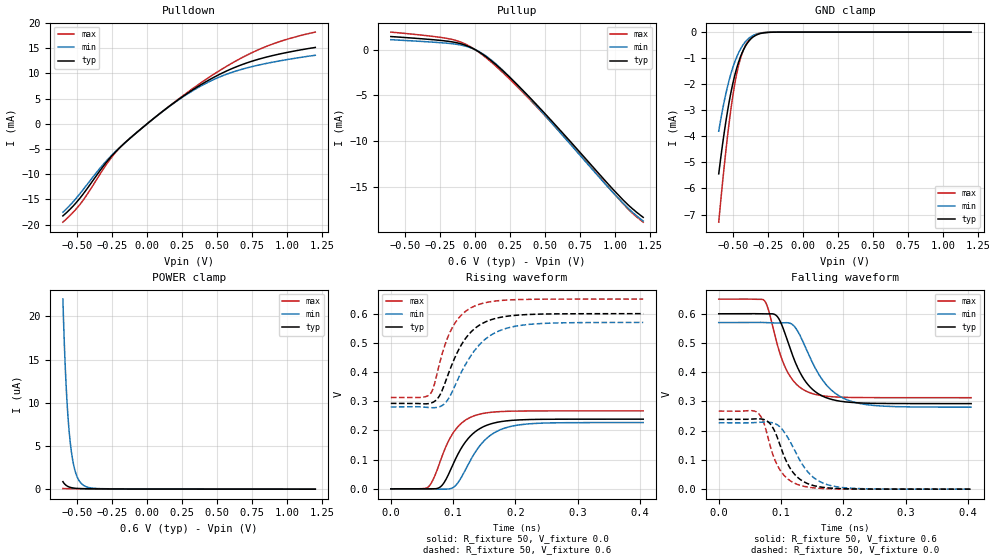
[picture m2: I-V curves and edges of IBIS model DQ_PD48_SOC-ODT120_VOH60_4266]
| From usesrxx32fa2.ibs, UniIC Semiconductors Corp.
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| DQ_PD48_SOC-ODT120_VOH60_4266
| (48 Ohm Pulldown, 120 Ohm System ODT Setting, VOH=VDDQ*0.60, 3200-4266Mbps)
[Model]   DQ_PD48_SOC-ODT120_VOH60_4266
Model_type   I/O
Vinl = 120.000mV
Vinh = 240.000mV
Vmeas = 180.000mV
Vref = 0.0mV
Cref = 0.0pF
Rref = 120.000Ohm
|   typ   min   max
|C_comp   0.834pF   0.784pF   0.884pF
C_comp_pullup   0.4170pF   0.3920pF   0.4420pF
C_comp_pulldown   0.4170pF   0.3920pF   0.4420pF
| Note: C_comp changes when the ODT circuit is enabled.
[Model Spec]
| Input threshold voltage corners
Vinl   0.1200V   0.1110V   0.1350V
Vinh   0.2400V   0.2310V   0.2550V
| Measurement voltage corners
Vmeas   0.1800V   0.1710V   0.1950V
| Timing spec test load voltage corners
Vref   0.0000V   0.0000V   0.0000V
| Dynamic Overshoot Parameters from LPDDR4_0P6 Specification
D_overshoot_ampl_h   0.30   NA   NA
D_overshoot_ampl_l   0.30   NA   NA
D_overshoot_area_h   0.1n   NA   NA
D_overshoot_area_l   0.1n   NA   NA
[Voltage Range]   0.6000V   0.5700V   0.6500V
[Pullup Reference]   0.6000V   0.5700V   0.6500V
| Junction Temperature (Ambient temp is 35C typ 95C min -40C max)
[Temperature Range]   50.0   110.0   -40.0
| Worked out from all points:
|   slope of the pulldown table from 0 to 0.09 V, typ, clamps not added: 44.5 ohm
|   slope of the pullup table from 0 to 0.09 V, typ, clamps not added: 98.8 ohm
|   GND clamp passes 1 mA (typ) near -0.45 V on its own axis
|   rising waveform, R_fixture 50, V_fixture 0.0: 20-80 % time 40.6ps typ, 44ps min, 35.7ps max; typ from 0 V to 0.239 V
|   falling waveform, R_fixture 50, V_fixture 0.6: 20-80 % time 39.2ps typ, 47.5ps min, 32.6ps max; typ from 0.6 V to 0.293 V
|   rising waveform, R_fixture 50, V_fixture 0.6: 20-80 % time 43.7ps typ, 51.6ps min, 35.4ps max; typ from 0.293 V to 0.6 V
|   falling waveform, R_fixture 50, V_fixture 0.0: 20-80 % time 31.7ps typ, 39.8ps min, 28.1ps max; typ from 0.239 V to 0 V
[Pulldown]
|   Voltage   I(typ)   I(min)   I(max)
-600mV    -18.26mA   -17.54mA   -19.51mA
-531.6mV  -16.44mA   -15.6mA    -17.67mA
-472.2mV  -14.52mA   -13.63mA   -15.77mA
-281.4mV  -7.339mA   -7.093mA   -7.724mA
-189.6mV  -4.59mA    -4.57mA    -4.601mA
85.8mV    1.925mA    1.914mA    1.931mA
310.8mV   6.479mA    6.321mA    6.697mA
417mV     8.313mA    8.002mA    8.761mA
525mV     9.929mA    9.39mA     10.7mA
764.4mV   12.57mA    11.46mA    14.34mA
971.4mV   14.02mA    12.62mA    16.55mA
1.2V      15.16mA    13.61mA    18.21mA
[GND Clamp]
|   Voltage   I(typ)   I(min)   I(max)
-600mV    -5.44mA    -3.802mA   -7.294mA
-567.6mV  -4.11mA    -2.837mA   -5.5mA
-535.2mV  -2.973mA   -2.046mA   -3.902mA
-506.4mV  -2.147mA   -1.48mA    -2.701mA
-481.2mV  -1.571mA   -1.083mA   -1.86mA
-454.2mV  -1.087mA   -747.7uA   -1.192mA
-421.8mV  -660.2uA   -454.9uA   -659.7uA
-389.4mV  -377uA     -257.1uA   -339.9uA
-357mV    -197.1uA   -136.6uA   -159.9uA
-292.2mV  -42.68uA   -31.8uA    -26.85uA
-195mV    -2.516uA   -2.429uA   -874.8nA
1.2V      0A         0A         0A
[Pullup]
|   Voltage   I(typ)   I(min)   I(max)
-600mV    1.424mA    1.081mA    1.912mA
-294mV    1.07mA     804.2uA    1.43mA
-146.4mV  795.9uA    607.4uA    1.042mA
-83.4mV   553.2uA    438.5uA    703.4uA
-18.6mV   146.8uA    121.9uA    180.2uA
87.6mV    -883.2uA   -806.4uA   -1.004mA
226.2mV   -2.721mA   -2.68mA    -2.925mA
413.4mV   -5.611mA   -5.73mA    -5.835mA
656.4mV   -9.666mA   -9.948mA   -9.9mA
980.4mV   -15.24mA   -15.59mA   -15.58mA
1.106V    -17.21mA   -17.58mA   -17.68mA
1.2V      -18.38mA   -18.78mA   -18.91mA
[POWER Clamp]
|   Voltage   I(typ)   I(min)   I(max)
-600mV    870.6nA    21.99uA    72.65nA
-594.6mV  739.5nA    19.12uA    70.4nA
-587.4mV  597.8nA    15.82uA    68.09nA
-574.8mV  417.8nA    11.31uA    64.22nA
-560.4mV  285.4nA    7.67uA     60.04nA
-546mV    201.7nA    5.188uA    56.09nA
-531.6mV  149nA      3.499uA    52.35nA
-511.8mV  105.9nA    2.043uA    47.56nA
-486.6mV  77.09nA    1.04uA     41.97nA
-456mV    59.8nA     477.6nA    35.93nA
-312mV    32.54nA    54.19nA    16.21nA
1.2V      0A         0A         0A
[Ramp]
|   typ   min   max
| 20% - 80%
dV/dt_r   143.21m/40.59p   136.24m/44.02p   160.27m/35.72p
dV/dt_f   184.34m/39.19p   173.66m/47.54p   202.23m/32.56p
| 25% - 75%
|dV/dt_r   119.34m/32.17p   113.54m/34.89p   133.56m/28.20p
|dV/dt_f   153.62m/30.99p   144.72m/37.66p   168.52m/25.70p
R_load = 50
[Rising Waveform]
R_fixture = 50
V_fixture = 0.0
|   Time   V(typ)   V(min)   V(max)
0s        75.42uV    60.11uV    39.23uV
58ps      -11.71uV   183.3uV    3.548mV
67ps      126.2uV    -347.1uV   28.22mV
79ps      6.01mV     -850.5uV   92.77mV
91ps      42.64mV    -691.5uV   157mV
104ps     103.1mV    11.71mV    203.5mV
135ps     195mV      124.1mV    251.2mV
162ps     223.6mV    186.7mV    262.5mV
199ps     235.4mV    216.8mV    266.3mV
405ps     238.8mV    227.1mV    267.2mV
[Falling Waveform]
R_fixture   = 50
V_fixture   = 0.6
V_fixture_min = 0.57
V_fixture_max = 0.65
|   Time   V(typ)   V(min)   V(max)
0s        600mV      570mV      650mV
73ps      599.6mV    570.2mV    645.9mV
80ps      599.8mV    569.5mV    611.9mV
93ps      592.9mV    568.4mV    502.6mV
108ps     522.5mV    569.6mV    410.9mV
124ps     428.2mV    549.7mV    360.2mV
144ps     355.6mV    462.4mV    331.7mV
174ps     311.7mV    353.6mV    317.7mV
214ps     296.6mV    299.6mV    313.7mV
405ps     292.8mV    280.6mV    313mV
[Rising Waveform]
R_fixture   = 50
V_fixture   = 0.6
V_fixture_min = 0.57
V_fixture_max = 0.65
|   Time   V(typ)   V(min)   V(max)
0s        292.7mV    280.5mV    312.9mV
63ps      293mV      278.3mV    324.5mV
69ps      298.1mV    278mV      351.2mV
78ps      318.4mV    281.1mV    428mV
97ps      420.1mV    326.2mV    545.4mV
115ps     499.7mV    407.1mV    598.9mV
135ps     549.7mV    475.5mV    626.7mV
163ps     580.7mV    529.5mV    642mV
203ps     595mV      558.1mV    648.2mV
405ps     600mV      570mV      650mV
[Falling Waveform]
R_fixture = 50
V_fixture = 0.0
|   Time   V(typ)   V(min)   V(max)
0s        238.8mV    227.2mV    267.2mV
63ps      240.8mV    228.7mV    260.7mV
72ps      238.5mV    229.7mV    229mV
82ps      224.9mV    228.8mV    151.6mV
96ps      165.3mV    217.1mV    73.97mV
112ps     81.03mV    172.2mV    33.08mV
130ps     34.46mV    99.54mV    13.53mV
154ps     11.34mV    36.95mV    4.158mV
187ps     2.651mV    9.038mV    888.7uV
405ps     143.9uV    152.4uV    60.13uV
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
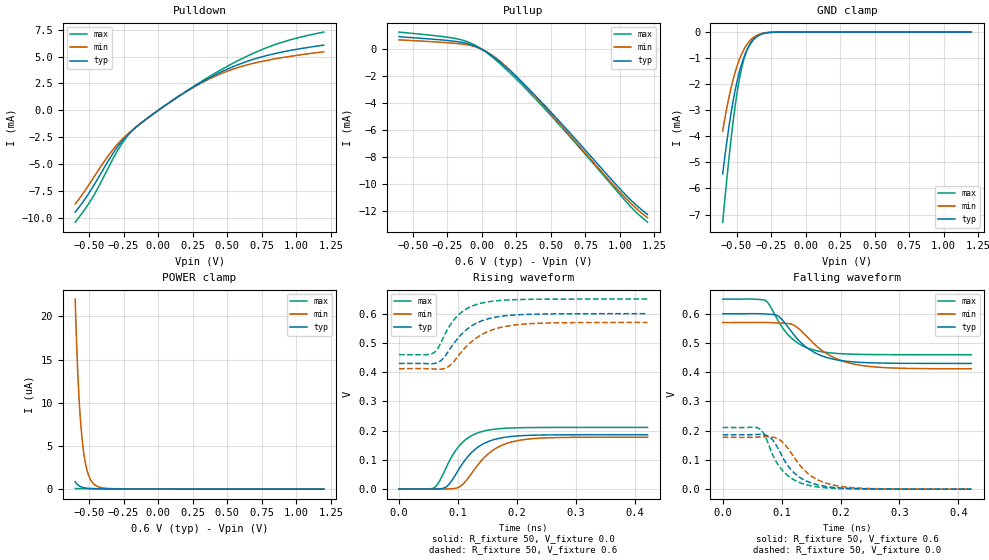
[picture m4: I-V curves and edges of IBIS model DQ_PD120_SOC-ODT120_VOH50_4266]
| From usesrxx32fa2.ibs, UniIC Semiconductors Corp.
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| DQ_PD120_SOC-ODT120_VOH50_4266
| (120 Ohm Pulldown, 120 Ohm System ODT Setting, VOH=VDDQ*0.50, 3200-4266Mbps)
[Model]   DQ_PD120_SOC-ODT120_VOH50_4266
Model_type   I/O
Vinl = 90.000mV
Vinh = 210.000mV
Vmeas = 150.000mV
Vref = 0.0mV
Cref = 0.0pF
Rref = 120.000Ohm
|   typ   min   max
|C_comp   0.834pF   0.784pF   0.884pF
C_comp_pullup   0.4170pF   0.3920pF   0.4420pF
C_comp_pulldown   0.4170pF   0.3920pF   0.4420pF
| Note: C_comp changes when the ODT circuit is enabled.
[Model Spec]
| Input threshold voltage corners
Vinl   0.0900V   0.0825V   0.1025V
Vinh   0.2100V   0.2025V   0.2225V
| Measurement voltage corners
Vmeas   0.1500V   0.1425V   0.1625V
| Timing spec test load voltage corners
Vref   0.0000V   0.0000V   0.0000V
| Dynamic Overshoot Parameters from LPDDR4_0P6 Specification
D_overshoot_ampl_h   0.30   NA   NA
D_overshoot_ampl_l   0.30   NA   NA
D_overshoot_area_h   0.1n   NA   NA
D_overshoot_area_l   0.1n   NA   NA
[Voltage Range]   0.6000V   0.5700V   0.6500V
[Pullup Reference]   0.6000V   0.5700V   0.6500V
| Junction Temperature (Ambient temp is 35C typ 95C min -40C max)
[Temperature Range]   50.0   110.0   -40.0
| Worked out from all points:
|   slope of the pulldown table from 0 to 0.09 V, typ, clamps not added: 112 ohm
|   slope of the pullup table from 0 to 0.09 V, typ, clamps not added: 150 ohm
|   GND clamp passes 1 mA (typ) near -0.45 V on its own axis
|   rising waveform, R_fixture 50, V_fixture 0.0: 20-80 % time 45.6ps typ, 50.2ps min, 40.1ps max; typ from 0 V to 0.186 V
|   falling waveform, R_fixture 50, V_fixture 0.6: 20-80 % time 52.6ps typ, 61.7ps min, 44.5ps max; typ from 0.6 V to 0.43 V
|   rising waveform, R_fixture 50, V_fixture 0.6: 20-80 % time 48.5ps typ, 54.3ps min, 40.5ps max; typ from 0.43 V to 0.6 V
|   falling waveform, R_fixture 50, V_fixture 0.0: 20-80 % time 41.8ps typ, 47.9ps min, 38.2ps max; typ from 0.186 V to 0 V
[Pulldown]
|   Voltage   I(typ)   I(min)   I(max)
-600mV    -9.425mA   -8.679mA   -10.37mA
-474mV    -7.132mA   -6.371mA   -8.069mA
-358.8mV  -4.645mA   -4.168mA   -5.281mA
-258mV    -2.791mA   -2.65mA    -3.009mA
-191.4mV  -1.905mA   -1.874mA   -1.937mA
-106.8mV  -1.012mA   -1.013mA   -997uA
217.2mV   1.868mA    1.841mA    1.899mA
352.2mV   2.881mA    2.801mA    2.991mA
494.4mV   3.789mA    3.608mA    4.047mA
674.4mV   4.68mA     4.322mA    5.213mA
845.4mV   5.274mA    4.781mA    6.101mA
1.2V      6.059mA    5.442mA    7.269mA
[GND Clamp]
|   Voltage   I(typ)   I(min)   I(max)
-600mV    -5.439mA   -3.802mA   -7.294mA
-565.8mV  -4.041mA   -2.789mA   -5.405mA
-535.2mV  -2.973mA   -2.046mA   -3.902mA
-508.2mV  -2.193mA   -1.513mA   -2.769mA
-483mV    -1.606mA   -1.109mA   -1.913mA
-456mV    -1.114mA   -767.7uA   -1.229mA
-425.4mV  -700.3uA   -480.9uA   -706.9uA
-394.8mV  -414.7uA   -284.1uA   -381.9uA
-358.8mV  -205.2uA   -141.2uA   -167.3uA
-303mV    -56.38uA   -40.97uA   -37.06uA
-200.4mV  -2.965uA   -2.834uA   -1.07uA
1.2V      0A         0A         0A
[Pullup]
|   Voltage   I(typ)   I(min)   I(max)
-600mV    931.5uA    702.4uA    1.276mA
-295.8mV  698.8uA    520.7uA    957.1uA
-148.2mV  521.6uA    393.6uA    701.6uA
-85.2mV   367.1uA    287.5uA    479.5uA
-25.8mV   130.8uA    107uA      165.6uA
80.4mV    -526.2uA   -474.5uA   -615.2uA
197.4mV   -1.525mA   -1.48mA    -1.689mA
366.6mV   -3.216mA   -3.264mA   -3.433mA
622.2mV   -6.02mA    -6.197mA   -6.295mA
980.4mV   -10.12mA   -10.36mA   -10.53mA
1.106V    -11.44mA   -11.68mA   -11.97mA
1.2V      -12.24mA   -12.48mA   -12.81mA
[POWER Clamp]
|   Voltage   I(typ)   I(min)   I(max)
-600mV    870.6nA    21.99uA    72.65nA
-594.6mV  739.5nA    19.12uA    70.4nA
-587.4mV  597.8nA    15.82uA    68.09nA
-574.8mV  418.3nA    11.31uA    64.22nA
-560.4mV  285nA      7.67uA     60.03nA
-546mV    201.8nA    5.191uA    56.09nA
-529.8mV  144nA      3.334uA    51.9nA
-511.8mV  105.9nA    2.043uA    47.55nA
-488.4mV  78.58nA    1.091uA    42.35nA
-459.6mV  61.25nA    519.8nA    36.6nA
-313.8mV  32.75nA    54.78nA    16.39nA
1.2V      0A         0A         0A
[Ramp]
|   typ   min   max
| 20% - 80%
dV/dt_r   111.52m/45.63p   106.50m/50.24p   126.61m/40.12p
dV/dt_f   101.96m/52.60p   94.93m/61.74p   114.05m/44.50p
| 25% - 75%
|dV/dt_r   92.93m/36.19p   88.75m/39.78p   105.51m/31.76p
|dV/dt_f   84.97m/41.69p   79.11m/48.97p   95.04m/35.23p
R_load = 50
[Rising Waveform]
R_fixture = 50
V_fixture = 0.0
|   Time   V(typ)   V(min)   V(max)
0s        84.39uV    73.65uV    42.32uV
58ps      13.39uV    -3.545uV   2.996mV
67ps      771.8uV    -234.2uV   21.24mV
78ps      5.003mV    36.3uV     64.55mV
107ps     84.62mV    14.05mV    158.2mV
124ps     126.6mV    55.95mV    183.5mV
145ps     156.6mV    108.4mV    199mV
175ps     175.7mV    150.1mV    207.4mV
215ps     183.5mV    170.1mV    210.3mV
422ps     185.9mV    177.6mV    211.1mV
[Falling Waveform]
R_fixture   = 50
V_fixture   = 0.6
V_fixture_min = 0.57
V_fixture_max = 0.65
|   Time   V(typ)   V(min)   V(max)
0s        600mV      570mV      650mV
72ps      599.4mV    570.4mV    646mV
79ps      598.6mV    569.9mV    631mV
94ps      592.1mV    568.1mV    576.4mV
115ps     543.1mV    565.4mV    519.9mV
136ps     495.4mV    535.8mV    490mV
160ps     463.1mV    488.2mV    473.3mV
196ps     441.5mV    443.8mV    463.9mV
240ps     433.1mV    422mV      460.8mV
422ps     430.1mV    411.8mV    459.9mV
[Rising Waveform]
R_fixture   = 50
V_fixture   = 0.6
V_fixture_min = 0.57
V_fixture_max = 0.65
|   Time   V(typ)   V(min)   V(max)
0s        430mV      411.7mV    459.9mV
59ps      429.4mV    410.3mV    466.3mV
67ps      434.3mV    409.7mV    484.5mV
81ps      462.5mV    415.5mV    540.9mV
99ps      513.5mV    451.4mV    592mV
119ps     552.3mV    496.9mV    621.4mV
142ps     576.6mV    530.2mV    637.2mV
172ps     590.7mV    552.8mV    645.4mV
215ps     597.5mV    564.9mV    648.9mV
422ps     600mV      570mV      650mV
[Falling Waveform]
R_fixture = 50
V_fixture = 0.0
|   Time   V(typ)   V(min)   V(max)
0s        186mV      177.7mV    211.1mV
59ps      187.4mV    178.2mV    209.9mV
77ps      181.4mV    179.4mV    157.4mV
89ps      156.7mV    176mV      100.6mV
104ps     100.7mV    156.1mV    58.32mV
123ps     52.59mV    103.6mV    29.67mV
145ps     25.25mV    53.09mV    13.51mV
174ps     9.727mV    21.39mV    4.862mV
215ps     2.635mV    6.071mV    1.213mV
422ps     170.7uV    179.6uV    63.72uV
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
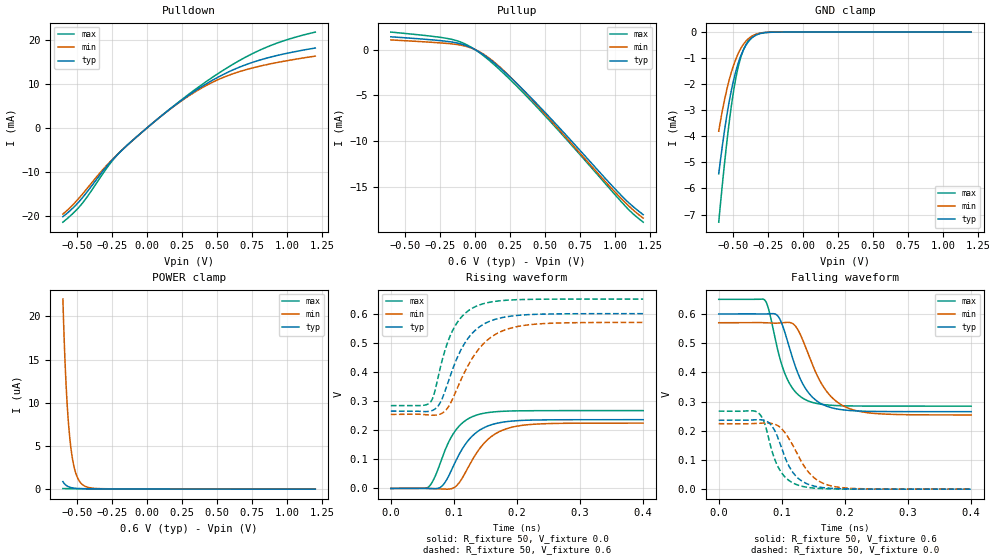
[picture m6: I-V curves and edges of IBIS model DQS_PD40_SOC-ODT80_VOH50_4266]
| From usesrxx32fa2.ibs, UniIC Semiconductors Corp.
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| DQS_PD40_SOC-ODT80_VOH50_4266
| (40 Ohm Pulldown, 80 Ohm System ODT Setting, VOH=VDDQ*0.50, 3200-4266Mbps)
[Model]   DQS_PD40_SOC-ODT80_VOH50_4266
Model_type   I/O
Vinl = 90.000mV
Vinh = 210.000mV
Vmeas = 150.000mV
Vref = 0.0mV
Cref = 0.0pF
Rref = 80.000Ohm
|   typ   min   max
|C_comp   0.849pF   0.799pF   0.899pF
C_comp_pullup   0.4245pF   0.3995pF   0.4495pF
C_comp_pulldown   0.4245pF   0.3995pF   0.4495pF
| Note: C_comp changes when the ODT circuit is enabled.
[Model Spec]
| Input threshold voltage corners
Vinl   0.0900V   0.0825V   0.1025V
Vinh   0.2100V   0.2025V   0.2225V
| Measurement voltage corners
Vmeas   0.1500V   0.1425V   0.1625V
| Timing spec test load voltage corners
Vref   0.0000V   0.0000V   0.0000V
| Dynamic Overshoot Parameters from LPDDR4_0P6 Specification
D_overshoot_ampl_h   0.30   NA   NA
D_overshoot_ampl_l   0.30   NA   NA
D_overshoot_area_h   0.1n   NA   NA
D_overshoot_area_l   0.1n   NA   NA
[Voltage Range]   0.6000V   0.5700V   0.6500V
[Pullup Reference]   0.6000V   0.5700V   0.6500V
| Junction Temperature (Ambient temp is 35C typ 95C min -40C max)
[Temperature Range]   50.0   110.0   -40.0
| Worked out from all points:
|   slope of the pulldown table from 0 to 0.09 V, typ, clamps not added: 37.5 ohm
|   slope of the pullup table from 0 to 0.09 V, typ, clamps not added: 101 ohm
|   GND clamp passes 1 mA (typ) near -0.45 V on its own axis
|   rising waveform, R_fixture 50, V_fixture 0.0: 20-80 % time 41ps typ, 44.5ps min, 35.6ps max; typ from 0 V to 0.236 V
|   falling waveform, R_fixture 50, V_fixture 0.6: 20-80 % time 36.2ps typ, 44.1ps min, 30ps max; typ from 0.6 V to 0.265 V
|   rising waveform, R_fixture 50, V_fixture 0.6: 20-80 % time 43.7ps typ, 51.9ps min, 35.3ps max; typ from 0.265 V to 0.6 V
|   falling waveform, R_fixture 50, V_fixture 0.0: 20-80 % time 30ps typ, 38.8ps min, 26.1ps max; typ from 0.236 V to 0 V
[Pulldown]
|   Voltage   I(typ)   I(min)   I(max)
-600mV    -20.17mA   -19.59mA   -21.44mA
-531.6mV  -18.32mA   -17.58mA   -19.54mA
-463.2mV  -15.97mA   -15.16mA   -17.21mA
-277.8mV  -8.396mA   -8.186mA   -8.74mA
-186mV    -5.294mA   -5.289mA   -5.284mA
85.8mV    2.286mA    2.274mA    2.29mA
336mV     8.248mA    8.034mA    8.544mA
449.4mV   10.51mA    10.08mA    11.12mA
548.4mV   12.21mA    11.52mA    13.19mA
780.6mV   15.18mA    13.84mA    17.31mA
985.8mV   16.86mA    15.19mA    19.9mA
1.2V      18.15mA    16.3mA     21.76mA
[GND Clamp]
|   Voltage   I(typ)   I(min)   I(max)
-600mV    -5.439mA   -3.802mA   -7.294mA
-565.8mV  -4.041mA   -2.789mA   -5.405mA
-535.2mV  -2.973mA   -2.046mA   -3.902mA
-508.2mV  -2.193mA   -1.512mA   -2.769mA
-481.2mV  -1.569mA   -1.083mA   -1.86mA
-456mV    -1.112mA   -767.2uA   -1.229mA
-427.2mV  -721.1uA   -494.7uA   -731.4uA
-394.8mV  -414.3uA   -283.7uA   -381.6uA
-360.6mV  -212.5uA   -146.7uA   -174.6uA
-301.2mV  -53.65uA   -39.09uA   -35.05uA
-196.8mV  -2.657uA   -2.564uA   -933.7nA
1.2V      0A         0A         0A
[Pullup]
|   Voltage   I(typ)   I(min)   I(max)
-600mV    1.396mA    1.053mA    1.912mA
-295.8mV  1.047mA    780.4uA    1.433mA
-139.2mV  754.9uA    572.2uA    1.011mA
-22.2mV   169.5uA    139uA      213.6uA
31.8mV    -278.8uA   -240.2uA   -337.5uA
87.6mV    -863.1uA   -782.8uA   -1.004mA
199.2mV   -2.285mA   -2.217mA   -2.53mA
366.6mV   -4.761mA   -4.826mA   -5.085mA
618.6mV   -8.842mA   -9.093mA   -9.253mA
996.6mV   -15.22mA   -15.57mA   -15.86mA
1.106V    -16.91mA   -17.26mA   -17.68mA
1.2V      -18.09mA   -18.46mA   -18.91mA
[POWER Clamp]
|   Voltage   I(typ)   I(min)   I(max)
-600mV    870.6nA    21.99uA    72.65nA
-589.2mV  630.1nA    16.59uA    68.66nA
-576.6mV  439.3nA    11.88uA    64.76nA
-564mV    313.2nA    8.461uA    61.06nA
-549.6mV  219.4nA    5.724uA    57.05nA
-533.4mV  154.4nA    3.674uA    52.81nA
-515.4mV  111.9nA    2.256uA    48.4nA
-492mV    81.69nA    1.201uA    43.12nA
-459.6mV  61.19nA    519.4nA    36.6nA
-407.4mV  46.25nA    163.2nA    27.8nA
-312mV    32.55nA    54.23nA    16.21nA
1.2V      0A         0A         0A
[Ramp]
|   typ   min   max
| 20% - 80%
dV/dt_r   141.55m/41.01p   134.50m/44.50p   160.28m/35.63p
dV/dt_f   200.71m/36.19p   189.47m/44.09p   219.38m/30.00p
| 25% - 75%
|dV/dt_r   117.96m/32.50p   112.08m/35.29p   133.56m/28.14p
|dV/dt_f   167.26m/28.62p   157.89m/34.92p   182.82m/23.63p
R_load = 50
[Rising Waveform]
R_fixture = 50
V_fixture = 0.0
|   Time   V(typ)   V(min)   V(max)
0s        58.42uV    39.04uV    33.21uV
59ps      -374.8uV   131.6uV    3.629mV
68ps      -728.1uV   -690.6uV   30.43mV
79ps      4.261mV    -1.727mV   90.14mV
92ps      42.99mV    -2.311mV   159.7mV
105ps     102.2mV    10.66mV    205.2mV
138ps     195.5mV    127.4mV    253mV
165ps     221.9mV    186mV      263.1mV
201ps     232.6mV    214mV      266.4mV
401ps     236mV      224.2mV    267.2mV
[Falling Waveform]
R_fixture   = 50
V_fixture   = 0.6
V_fixture_min = 0.57
V_fixture_max = 0.65
|   Time   V(typ)   V(min)   V(max)
0s        600mV      570mV      650mV
73ps      599.8mV    570.1mV    647.8mV
80ps      600.5mV    569.3mV    610.5mV
93ps      595mV      568.6mV    483.5mV
107ps     523.5mV    571mV      385.8mV
123ps     412.6mV    555.4mV    330.2mV
142ps     331.9mV    463.7mV    302.2mV
171ps     284.5mV    336.1mV    288.6mV
206ps     269.7mV    277.3mV    285.2mV
401ps     265.5mV    254.2mV    284.4mV
[Rising Waveform]
R_fixture   = 50
V_fixture   = 0.6
V_fixture_min = 0.57
V_fixture_max = 0.65
|   Time   V(typ)   V(min)   V(max)
0s        265.4mV    254.1mV    284.4mV
63ps      265.7mV    251.8mV    296.3mV
69ps      271mV      251.4mV    325.8mV
79ps      296.3mV    255.5mV    418mV
98ps      408.5mV    306.5mV    541.2mV
117ps     497.1mV    398.3mV    599mV
138ps     549.9mV    473.6mV    627.5mV
166ps     580.6mV    528.6mV    642.3mV
206ps     594.8mV    557.7mV    648.2mV
401ps     600mV      569.9mV    650mV
[Falling Waveform]
R_fixture = 50
V_fixture = 0.0
|   Time   V(typ)   V(min)   V(max)
0s        236mV      224.3mV    267.2mV
64ps      237.9mV    225.9mV    259.3mV
73ps      235.3mV    226.8mV    224.8mV
82ps      222.9mV    225.8mV    150.6mV
96ps      164.8mV    214.4mV    69.3mV
112ps     77.45mV    171.4mV    29.07mV
128ps     34.09mV    107.6mV    12.37mV
152ps     10.35mV    38.22mV    3.517mV
185ps     2.214mV    8.482mV    706.9uV
401ps     129.7uV    135.4uV    54.98uV
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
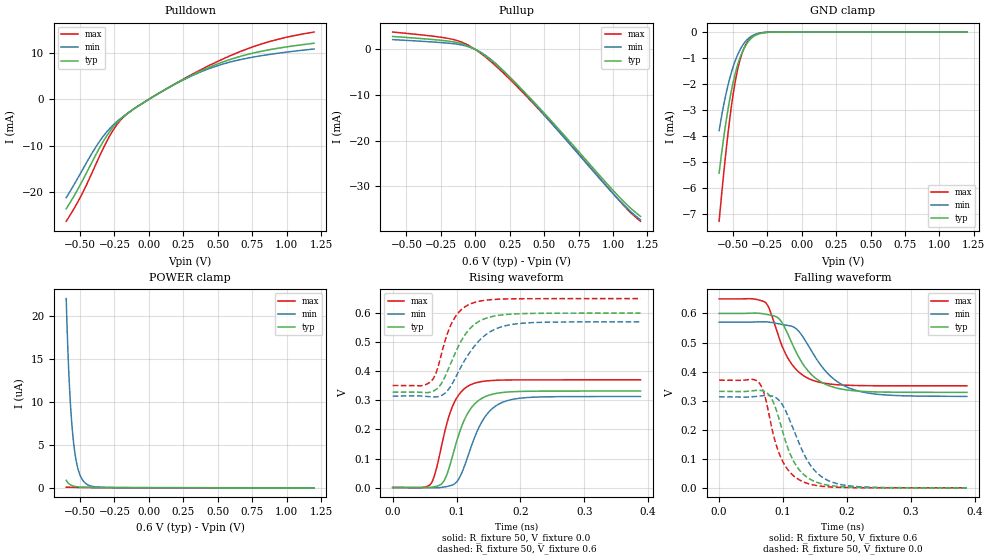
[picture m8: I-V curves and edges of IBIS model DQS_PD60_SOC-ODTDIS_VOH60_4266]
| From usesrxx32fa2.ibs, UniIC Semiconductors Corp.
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| DQS_PD60_SOC-ODTDIS_VOH60_4266
| (60 Ohm Pulldown, SOC ODT disabled setting, VOH=VDDQ*0.60 cal. point, 3200-4266Mbps)
[Model]   DQS_PD60_SOC-ODTDIS_VOH60_4266
Model_type   I/O
Vinl = 120.000mV
Vinh = 240.000mV
Vmeas = 180.000mV
Vref = 0.0mV
Cref = 0.0pF
|   typ   min   max
|C_comp   0.849pF   0.799pF   0.899pF
C_comp_pullup   0.4245pF   0.3995pF   0.4495pF
C_comp_pulldown   0.4245pF   0.3995pF   0.4495pF
| Note: C_comp changes when the ODT circuit is enabled.
[Model Spec]
| Input threshold voltage corners
Vinl   0.1200V   0.1110V   0.1350V
Vinh   0.2400V   0.2310V   0.2550V
| Measurement voltage corners
Vmeas   0.1800V   0.1710V   0.1950V
| Timing spec test load voltage corners
Vref   0.0000V   0.0000V   0.0000V
| Dynamic Overshoot Parameters from LPDDR4_0P6 Specification
D_overshoot_ampl_h   0.30   NA   NA
D_overshoot_ampl_l   0.30   NA   NA
D_overshoot_area_h   0.1n   NA   NA
D_overshoot_area_l   0.1n   NA   NA
[Voltage Range]   0.6000V   0.5700V   0.6500V
[Pullup Reference]   0.6000V   0.5700V   0.6500V
| Junction Temperature (Ambient temp is 35C typ 95C min -40C max)
[Temperature Range]   50.0   110.0   -40.0
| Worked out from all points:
|   slope of the pulldown table from 0 to 0.09 V, typ, clamps not added: 55.7 ohm
|   slope of the pullup table from 0 to 0.09 V, typ, clamps not added: 49.6 ohm
|   GND clamp passes 1 mA (typ) near -0.45 V on its own axis
|   rising waveform, R_fixture 50, V_fixture 0.0: 20-80 % time 32.1ps typ, 36.5ps min, 27.7ps max; typ from 0 V to 0.332 V
|   falling waveform, R_fixture 50, V_fixture 0.6: 20-80 % time 43.9ps typ, 53.4ps min, 36.3ps max; typ from 0.6 V to 0.328 V
|   rising waveform, R_fixture 50, V_fixture 0.6: 20-80 % time 38.3ps typ, 46.5ps min, 28.4ps max; typ from 0.328 V to 0.6 V
|   falling waveform, R_fixture 50, V_fixture 0.0: 20-80 % time 34ps typ, 41.2ps min, 30ps max; typ from 0.332 V to 0 V
[Pulldown]
|   Voltage   I(typ)   I(min)   I(max)
-600mV    -23.68mA   -21.28mA   -26.38mA
-486.6mV  -17.86mA   -15.49mA   -20.56mA
-396.6mV  -12.66mA   -10.87mA   -14.83mA
-339mV    -9.524mA   -8.316mA   -11.1mA
-241.8mV  -5.413mA   -5.085mA   -5.89mA
-191.4mV  -3.947mA   -3.838mA   -4.06mA
-141mV    -2.767mA   -2.744mA   -2.751mA
184.8mV   3.217mA    3.178mA    3.26mA
465.6mV   7.247mA    6.93mA     7.703mA
645.6mV   9.122mA    8.458mA    10.1mA
814.8mV   10.37mA    9.421mA    11.94mA
1.2V      12.12mA    10.89mA    14.55mA
[GND Clamp]
|   Voltage   I(typ)   I(min)   I(max)
-600mV    -5.44mA    -3.803mA   -7.294mA
-565.8mV  -4.041mA   -2.789mA   -5.405mA
-537mV    -3.031mA   -2.085mA   -3.984mA
-508.2mV  -2.194mA   -1.512mA   -2.769mA
-481.2mV  -1.569mA   -1.084mA   -1.86mA
-452.4mV  -1.056mA   -728.2uA   -1.155mA
-427.2mV  -720.4uA   -495.1uA   -731.4uA
-393mV    -402.8uA   -274.8uA   -367.4uA
-357mV    -199.1uA   -135.9uA   -159.6uA
-303mV    -56.27uA   -40.83uA   -37uA
-211.2mV  -4.173uA   -3.861uA   -1.653uA
1.2V      0A         0A         0A
[Pullup]
|   Voltage   I(typ)   I(min)   I(max)
-600mV    2.847mA    2.16mA     3.822mA
-290.4mV  2.129mA    1.598mA    2.844mA
-146.4mV  1.59mA     1.214mA    2.08mA
-87mV     1.14mA     901.5uA    1.451mA
-25.8mV   398.8uA    329.7uA    491.6uA
78.6mV    -1.552mA   -1.407mA   -1.775mA
208.2mV   -4.898mA   -4.79mA    -5.294mA
402.6mV   -10.81mA   -11.02mA   -11.26mA
634.8mV   -18.47mA   -19mA      -18.94mA
989.4mV   -30.58mA   -31.27mA   -31.27mA
1.11V     -34.34mA   -35.06mA   -35.28mA
1.2V      -36.67mA   -37.44mA   -37.73mA
[POWER Clamp]
|   Voltage   I(typ)   I(min)   I(max)
-600mV    870.6nA    21.99uA    72.65nA
-589.2mV  630nA      16.59uA    68.66nA
-576.6mV  439.8nA    11.87uA    64.76nA
-562.2mV  298.7nA    8.051uA    60.55nA
-549.6mV  220.1nA    5.714uA    57.05nA
-533.4mV  154.9nA    3.673uA    52.81nA
-510mV    103.1nA    1.946uA    47.14nA
-486.6mV  77.12nA    1.042uA    41.97nA
-459.6mV  61.19nA    520.8nA    36.6nA
-409.2mV  46.61nA    168.8nA    28.07nA
-310.2mV  32.36nA    53.64nA    16.04nA
1.2V      0A         0A         0A
[Ramp]
|   typ   min   max
| 20% - 80%
dV/dt_r   199.03m/32.08p   187.80m/36.47p   222.26m/27.74p
dV/dt_f   162.95m/43.94p   153.14m/53.41p   179.40m/36.34p
| 25% - 75%
|dV/dt_r   165.86m/25.36p   156.50m/28.86p   185.22m/21.90p
|dV/dt_f   135.79m/34.71p   127.62m/42.18p   149.50m/28.70p
R_load = 50
[Rising Waveform]
R_fixture = 50
V_fixture = 0.0
|   Time   V(typ)   V(min)   V(max)
0s        207.4uV    193.9uV    95.94uV
60ps      881.9uV    -606uV     13.47mV
68ps      4.326mV    -863.2uV   61.04mV
79ps      18.54mV    1.367mV    168.1mV
93ps      102.9mV    8.369mV    275.6mV
106ps     198.6mV    39.86mV    326.3mV
123ps     274mV      141.3mV    354.7mV
147ps     314.8mV    250.7mV    366.9mV
178ps     328.4mV    298.1mV    370mV
388ps     331.9mV    313.2mV    370.5mV
[Falling Waveform]
R_fixture   = 50
V_fixture   = 0.6
V_fixture_min = 0.57
V_fixture_max = 0.65
|   Time   V(typ)   V(min)   V(max)
0s        600mV      570mV      650mV
73ps      597.5mV    571.1mV    636.8mV
80ps      594.1mV    569.7mV    607.7mV
94ps      581.4mV    564mV      514.5mV
109ps     522.3mV    558.5mV    441.3mV
125ps     448.6mV    537.8mV    397.9mV
148ps     382.8mV    458.6mV    369mV
178ps     346.9mV    377.1mV    356.1mV
216ps     333.1mV    334.3mV    352mV
388ps     328.4mV    314.8mV    351mV
[Rising Waveform]
R_fixture   = 50
V_fixture   = 0.6
V_fixture_min = 0.57
V_fixture_max = 0.65
|   Time   V(typ)   V(min)   V(max)
0s        328.4mV    314.6mV    351mV
61ps      329.4mV    311.9mV    367.6mV
68ps      337.6mV    311.9mV    394.6mV
76ps      357.2mV    316.3mV    456.8mV
94ps      443.2mV    360.2mV    572.5mV
110ps     514.5mV    427.5mV    616.7mV
125ps     555.5mV    478mV      634.6mV
152ps     586.5mV    535.2mV    645.9mV
187ps     596.9mV    561.2mV    649.2mV
388ps     600mV      570mV      650mV
[Falling Waveform]
R_fixture = 50
V_fixture = 0.0
|   Time   V(typ)   V(min)   V(max)
0s        332mV      313.3mV    370.6mV
59ps      335.5mV    314.9mV    368.5mV
68ps      334mV      317.3mV    339.9mV
77ps      322.6mV    317.8mV    264.9mV
99ps      197.3mV    286.3mV    93.39mV
114ps     103mV      214.5mV    46.7mV
132ps     46.56mV    119.7mV    20.5mV
156ps     16.74mV    45.92mV    6.982mV
190ps     4.211mV    11.62mV    1.593mV
388ps     256.5uV    266.1uV    116.6uV
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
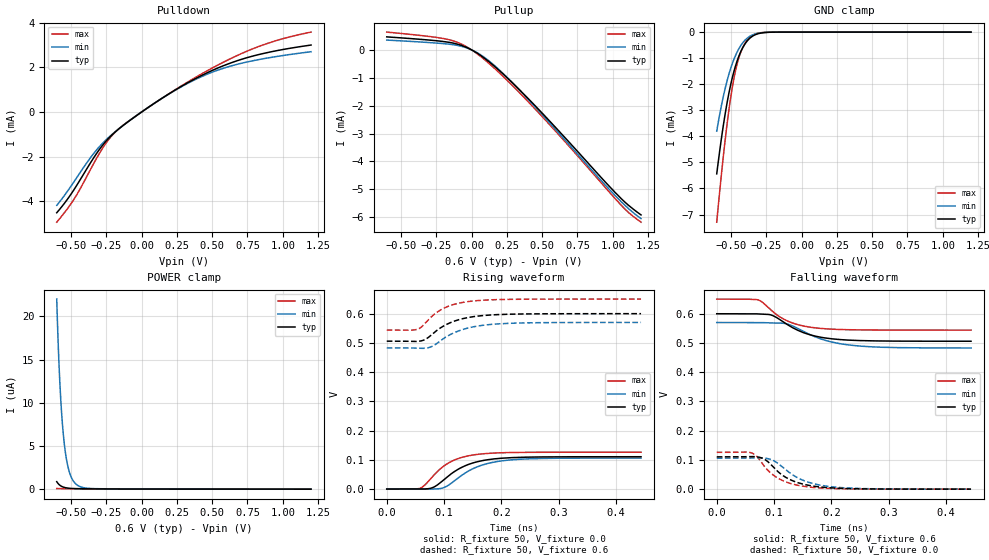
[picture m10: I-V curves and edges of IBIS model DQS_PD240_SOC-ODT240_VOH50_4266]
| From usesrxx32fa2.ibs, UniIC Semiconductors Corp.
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| DQS_PD240_SOC-ODT240_VOH50_4266
| (240 Ohm Pulldown, 240 Ohm System ODT Setting, VOH=VDDQ*0.50, 3200-4266Mbps)
[Model]   DQS_PD240_SOC-ODT240_VOH50_4266
Model_type   I/O
Vinl = 90.000mV
Vinh = 210.000mV
Vmeas = 150.000mV
Vref = 0.0mV
Cref = 0.0pF
Rref = 240.000Ohm
|   typ   min   max
|C_comp   0.849pF   0.799pF   0.899pF
C_comp_pullup   0.4245pF   0.3995pF   0.4495pF
C_comp_pulldown   0.4245pF   0.3995pF   0.4495pF
| Note: C_comp changes when the ODT circuit is enabled.
[Model Spec]
| Input threshold voltage corners
Vinl   0.0900V   0.0825V   0.1025V
Vinh   0.2100V   0.2025V   0.2225V
| Measurement voltage corners
Vmeas   0.1500V   0.1425V   0.1625V
| Timing spec test load voltage corners
Vref   0.0000V   0.0000V   0.0000V
| Dynamic Overshoot Parameters from LPDDR4_0P6 Specification
D_overshoot_ampl_h   0.30   NA   NA
D_overshoot_ampl_l   0.30   NA   NA
D_overshoot_area_h   0.1n   NA   NA
D_overshoot_area_l   0.1n   NA   NA
[Voltage Range]   0.6000V   0.5700V   0.6500V
[Pullup Reference]   0.6000V   0.5700V   0.6500V
| Junction Temperature (Ambient temp is 35C typ 95C min -40C max)
[Temperature Range]   50.0   110.0   -40.0
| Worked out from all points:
|   slope of the pulldown table from 0 to 0.09 V, typ, clamps not added: 230 ohm
|   slope of the pullup table from 0 to 0.09 V, typ, clamps not added: 306 ohm
|   GND clamp passes 1 mA (typ) near -0.45 V on its own axis
|   rising waveform, R_fixture 50, V_fixture 0.0: 20-80 % time 55.1ps typ, 57.6ps min, 47.8ps max; typ from 0 V to 0.111 V
|   falling waveform, R_fixture 50, V_fixture 0.6: 20-80 % time 60.1ps typ, 69.3ps min, 51.3ps max; typ from 0.6 V to 0.506 V
|   rising waveform, R_fixture 50, V_fixture 0.6: 20-80 % time 52.7ps typ, 56.2ps min, 46.4ps max; typ from 0.506 V to 0.6 V
|   falling waveform, R_fixture 50, V_fixture 0.0: 20-80 % time 49.3ps typ, 55ps min, 45.3ps max; typ from 0.111 V to 0 V
[Pulldown]
|   Voltage   I(typ)   I(min)   I(max)
-600mV    -4.517mA   -4.184mA   -4.94mA
-472.2mV  -3.424mA   -3.071mA   -3.853mA
-353.4mV  -2.2mA     -1.981mA   -2.485mA
-256.2mV  -1.342mA   -1.276mA   -1.439mA
-187.8mV  -903uA     -890.3uA   -911.6uA
-105mV    -481.2uA   -482.3uA   -471uA
217.2mV   905.8uA    896.2uA    913.4uA
357.6mV   1.419mA    1.386mA    1.461mA
501.6mV   1.869mA    1.79mA     1.978mA
679.8mV   2.307mA    2.145mA    2.542mA
850.8mV   2.609mA    2.377mA    2.989mA
1.2V      3.005mA    2.705mA    3.586mA
[GND Clamp]
|   Voltage   I(typ)   I(min)   I(max)
-600mV    -5.439mA   -3.802mA   -7.294mA
-567.6mV  -4.109mA   -2.837mA   -5.5mA
-537mV    -3.03mA    -2.085mA   -3.984mA
-510mV    -2.241mA   -1.544mA   -2.838mA
-483mV    -1.606mA   -1.109mA   -1.913mA
-459.6mV  -1.172mA   -808.3uA   -1.309mA
-427.2mV  -721uA     -495.7uA   -732.1uA
-393mV    -401.2uA   -276.2uA   -367.8uA
-360.6mV  -212.3uA   -146.9uA   -174.6uA
-304.8mV  -58.68uA   -42.78uA   -38.98uA
-227.4mV  -6.862uA   -6.173uA   -3.032uA
1.2V      0A         0A         0A
[Pullup]
|   Voltage   I(typ)   I(min)   I(max)
-600mV    465uA      350.7uA    636.6uA
-283.2mV  342.9uA    255.6uA    469.1uA
-144.6mV  256.3uA    193.8uA    343.8uA
-85.2mV   182.1uA    142.7uA    237.5uA
-22.2mV   56.19uA    46.13uA    70.78uA
80.4mV    -258.5uA   -233uA     -301.9uA
170.4mV   -625uA     -597.7uA   -699.1uA
280.2mV   -1.136mA   -1.131mA   -1.233mA
591.6mV   -2.763mA   -2.837mA   -2.897mA
1.016V    -5.111mA   -5.221mA   -5.331mA
1.106V    -5.551mA   -5.668mA   -5.807mA
1.2V      -5.919mA   -6.049mA   -6.179mA
[POWER Clamp]
|   Voltage   I(typ)   I(min)   I(max)
-600mV    870.6nA    21.99uA    72.65nA
-589.2mV  630.3nA    16.59uA    68.66nA
-576.6mV  439.2nA    11.89uA    64.76nA
-562.2mV  298.6nA    8.05uA     60.54nA
-549.6mV  219.1nA    5.718uA    57.05nA
-531.6mV  149.6nA    3.497uA    52.35nA
-513.6mV  108.8nA    2.141uA    47.98nA
-488.4mV  78.66nA    1.093uA    42.35nA
-459.6mV  61.23nA    522.3nA    36.6nA
-412.8mV  47.34nA    181.2nA    28.62nA
-312mV    32.55nA    54.21nA    16.21nA
1.2V      0A         0A         0A
[Ramp]
|   typ   min   max
| 20% - 80%
dV/dt_r   66.27m/55.15p   63.56m/57.61p   75.63m/47.78p
dV/dt_f   56.43m/60.06p   52.26m/69.27p   63.60m/51.28p
| 25% - 75%
|dV/dt_r   55.23m/43.74p   52.97m/45.63p   63.02m/37.88p
|dV/dt_f   47.02m/47.61p   43.55m/55.11p   53.00m/40.56p
R_load = 50
[Rising Waveform]
R_fixture = 50
V_fixture = 0.0
|   Time   V(typ)   V(min)   V(max)
0s        49.81uV    41.85uV    25.88uV
57ps      -142.4uV   -119.4uV   2.005mV
78ps      3.452mV    -148.3uV   38.17mV
97ps      27.39mV    3.206mV    74.72mV
111ps     49.83mV    17.47mV    92.63mV
133ps     76.26mV    49.78mV    109.3mV
153ps     90.76mV    71.88mV    117.3mV
187ps     103mV      92.11mV    123.1mV
233ps     108.5mV    102mV      125.4mV
444ps     110.5mV    106mV      126.1mV
[Falling Waveform]
R_fixture   = 50
V_fixture   = 0.6
V_fixture_min = 0.57
V_fixture_max = 0.65
|   Time   V(typ)   V(min)   V(max)
0s        600mV      570mV      650mV
72ps      599.4mV    570.2mV    647.5mV
80ps      598.9mV    569.7mV    638.8mV
96ps      595mV      568.5mV    610.4mV
120ps     567.1mV    566.3mV    578.5mV
145ps     540.4mV    546.1mV    560.8mV
171ps     523.9mV    521.7mV    551.9mV
208ps     512.8mV    500.2mV    546.7mV
257ps     507.9mV    488.4mV    544.6mV
444ps     506mV      482.9mV    544mV
[Rising Waveform]
R_fixture   = 50
V_fixture   = 0.6
V_fixture_min = 0.57
V_fixture_max = 0.65
|   Time   V(typ)   V(min)   V(max)
0s        505.9mV    482.8mV    544mV
52ps      505mV      481.9mV    545.9mV
60ps      506.9mV    481.3mV    553.6mV
72ps      517.8mV    483.3mV    578.1mV
87ps      542.1mV    497.4mV    603.8mV
102ps     560.8mV    518.5mV    620.9mV
121ps     576.5mV    537.6mV    633.7mV
144ps     587.5mV    552mV      641.9mV
221ps     598.5mV    567.5mV    649.2mV
444ps     600mV      570mV      650mV
[Falling Waveform]
R_fixture = 50
V_fixture = 0.0
|   Time   V(typ)   V(min)   V(max)
0s        110.6mV    106.1mV    126.1mV
58ps      111.5mV    106.5mV    125.6mV
68ps      111mV      107.1mV    115.7mV
77ps      107.7mV    107.1mV    94.86mV
91ps      91.04mV    103.6mV    61.16mV
107ps     59.83mV    88.03mV    37.53mV
127ps     33.62mV    56.63mV    20.58mV
153ps     16.19mV    28.59mV    9.353mV
229ps     2.033mV    3.946mV    984.4uV
444ps     119.1uV    143uV      42.69uV
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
